VERSION 5.7 ;
BUSBITCHARS "[]" ;
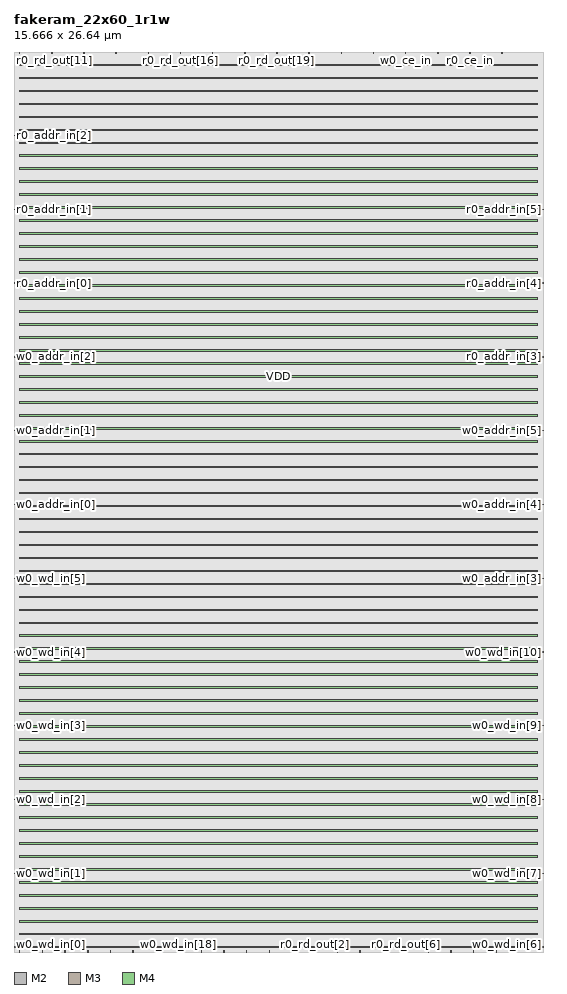
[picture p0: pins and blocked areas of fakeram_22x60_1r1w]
MACRO fakeram_22x60_1r1w
  FOREIGN fakeram_22x60_1r1w 0 0 ;
  SYMMETRY X Y R90 ;
  SIZE 15.666 BY 26.640 ;
  CLASS BLOCK ;
  PIN w0_wd_in[0]
    DIRECTION INPUT ;
    USE SIGNAL ;
    SHAPE ABUTMENT ;
    PORT
      LAYER M2 ;
      RECT 0.000 0.138 0.036 0.150 ;
    END
  END w0_wd_in[0]
  PIN w0_wd_in[1]
    DIRECTION INPUT ;
    USE SIGNAL ;
    SHAPE ABUTMENT ;
    PORT
      LAYER M2 ;
      RECT 0.000 2.322 0.036 2.334 ;
    END
  END w0_wd_in[1]
  PIN w0_wd_in[2]
    DIRECTION INPUT ;
    USE SIGNAL ;
    SHAPE ABUTMENT ;
    PORT
      LAYER M2 ;
      RECT 0.000 4.506 0.036 4.518 ;
    END
  END w0_wd_in[2]
  PIN w0_wd_in[3]
    DIRECTION INPUT ;
    USE SIGNAL ;
    SHAPE ABUTMENT ;
    PORT
      LAYER M2 ;
      RECT 0.000 6.690 0.036 6.702 ;
    END
  END w0_wd_in[3]
  PIN w0_wd_in[4]
    DIRECTION INPUT ;
    USE SIGNAL ;
    SHAPE ABUTMENT ;
    PORT
      LAYER M2 ;
      RECT 0.000 8.874 0.036 8.886 ;
    END
  END w0_wd_in[4]
  PIN w0_wd_in[5]
    DIRECTION INPUT ;
    USE SIGNAL ;
    SHAPE ABUTMENT ;
    PORT
      LAYER M2 ;
      RECT 0.000 11.058 0.036 11.070 ;
    END
  END w0_wd_in[5]
  PIN w0_wd_in[6]
    DIRECTION INPUT ;
    USE SIGNAL ;
    SHAPE ABUTMENT ;
    PORT
      LAYER M2 ;
      RECT 15.630 0.138 15.666 0.150 ;
    END
  END w0_wd_in[6]
  PIN w0_wd_in[7]
    DIRECTION INPUT ;
    USE SIGNAL ;
    SHAPE ABUTMENT ;
    PORT
      LAYER M2 ;
      RECT 15.630 2.322 15.666 2.334 ;
    END
  END w0_wd_in[7]
  PIN w0_wd_in[8]
    DIRECTION INPUT ;
    USE SIGNAL ;
    SHAPE ABUTMENT ;
    PORT
      LAYER M2 ;
      RECT 15.630 4.506 15.666 4.518 ;
    END
  END w0_wd_in[8]
  PIN w0_wd_in[9]
    DIRECTION INPUT ;
    USE SIGNAL ;
    SHAPE ABUTMENT ;
    PORT
      LAYER M2 ;
      RECT 15.630 6.690 15.666 6.702 ;
    END
  END w0_wd_in[9]
  PIN w0_wd_in[10]
    DIRECTION INPUT ;
    USE SIGNAL ;
    SHAPE ABUTMENT ;
    PORT
      LAYER M2 ;
      RECT 15.630 8.874 15.666 8.886 ;
    END
  END w0_wd_in[10]
  PIN w0_wd_in[11]
    DIRECTION INPUT ;
    USE SIGNAL ;
    SHAPE ABUTMENT ;
    PORT
      LAYER M3 ;
      RECT 0.161 0.000 0.175 0.042 ;
    END
  END w0_wd_in[11]
  PIN w0_wd_in[12]
    DIRECTION INPUT ;
    USE SIGNAL ;
    SHAPE ABUTMENT ;
    PORT
      LAYER M3 ;
      RECT 0.833 0.000 0.847 0.042 ;
    END
  END w0_wd_in[12]
  PIN w0_wd_in[13]
    DIRECTION INPUT ;
    USE SIGNAL ;
    SHAPE ABUTMENT ;
    PORT
      LAYER M3 ;
      RECT 1.505 0.000 1.519 0.042 ;
    END
  END w0_wd_in[13]
  PIN w0_wd_in[14]
    DIRECTION INPUT ;
    USE SIGNAL ;
    SHAPE ABUTMENT ;
    PORT
      LAYER M3 ;
      RECT 2.177 0.000 2.191 0.042 ;
    END
  END w0_wd_in[14]
  PIN w0_wd_in[15]
    DIRECTION INPUT ;
    USE SIGNAL ;
    SHAPE ABUTMENT ;
    PORT
      LAYER M3 ;
      RECT 2.849 0.000 2.863 0.042 ;
    END
  END w0_wd_in[15]
  PIN w0_wd_in[16]
    DIRECTION INPUT ;
    USE SIGNAL ;
    SHAPE ABUTMENT ;
    PORT
      LAYER M3 ;
      RECT 3.521 0.000 3.535 0.042 ;
    END
  END w0_wd_in[16]
  PIN w0_wd_in[17]
    DIRECTION INPUT ;
    USE SIGNAL ;
    SHAPE ABUTMENT ;
    PORT
      LAYER M3 ;
      RECT 4.193 0.000 4.207 0.042 ;
    END
  END w0_wd_in[17]
  PIN w0_wd_in[18]
    DIRECTION INPUT ;
    USE SIGNAL ;
    SHAPE ABUTMENT ;
    PORT
      LAYER M3 ;
      RECT 4.865 0.000 4.879 0.042 ;
    END
  END w0_wd_in[18]
  PIN w0_wd_in[19]
    DIRECTION INPUT ;
    USE SIGNAL ;
    SHAPE ABUTMENT ;
    PORT
      LAYER M3 ;
      RECT 5.537 0.000 5.551 0.042 ;
    END
  END w0_wd_in[19]
  PIN w0_wd_in[20]
    DIRECTION INPUT ;
    USE SIGNAL ;
    SHAPE ABUTMENT ;
    PORT
      LAYER M3 ;
      RECT 6.209 0.000 6.223 0.042 ;
    END
  END w0_wd_in[20]
  PIN w0_wd_in[21]
    DIRECTION INPUT ;
    USE SIGNAL ;
    SHAPE ABUTMENT ;
    PORT
      LAYER M3 ;
      RECT 6.881 0.000 6.895 0.042 ;
    END
  END w0_wd_in[21]
  PIN r0_rd_out[0]
    DIRECTION OUTPUT ;
    USE SIGNAL ;
    SHAPE ABUTMENT ;
    PORT
      LAYER M3 ;
      RECT 7.553 0.000 7.567 0.042 ;
    END
  END r0_rd_out[0]
  PIN r0_rd_out[1]
    DIRECTION OUTPUT ;
    USE SIGNAL ;
    SHAPE ABUTMENT ;
    PORT
      LAYER M3 ;
      RECT 8.225 0.000 8.239 0.042 ;
    END
  END r0_rd_out[1]
  PIN r0_rd_out[2]
    DIRECTION OUTPUT ;
    USE SIGNAL ;
    SHAPE ABUTMENT ;
    PORT
      LAYER M3 ;
      RECT 8.897 0.000 8.911 0.042 ;
    END
  END r0_rd_out[2]
  PIN r0_rd_out[3]
    DIRECTION OUTPUT ;
    USE SIGNAL ;
    SHAPE ABUTMENT ;
    PORT
      LAYER M3 ;
      RECT 9.569 0.000 9.583 0.042 ;
    END
  END r0_rd_out[3]
  PIN r0_rd_out[4]
    DIRECTION OUTPUT ;
    USE SIGNAL ;
    SHAPE ABUTMENT ;
    PORT
      LAYER M3 ;
      RECT 10.241 0.000 10.255 0.042 ;
    END
  END r0_rd_out[4]
  PIN r0_rd_out[5]
    DIRECTION OUTPUT ;
    USE SIGNAL ;
    SHAPE ABUTMENT ;
    PORT
      LAYER M3 ;
      RECT 10.913 0.000 10.927 0.042 ;
    END
  END r0_rd_out[5]
  PIN r0_rd_out[6]
    DIRECTION OUTPUT ;
    USE SIGNAL ;
    SHAPE ABUTMENT ;
    PORT
      LAYER M3 ;
      RECT 11.585 0.000 11.599 0.042 ;
    END
  END r0_rd_out[6]
  PIN r0_rd_out[7]
    DIRECTION OUTPUT ;
    USE SIGNAL ;
    SHAPE ABUTMENT ;
    PORT
      LAYER M3 ;
      RECT 12.257 0.000 12.271 0.042 ;
    END
  END r0_rd_out[7]
  PIN r0_rd_out[8]
    DIRECTION OUTPUT ;
    USE SIGNAL ;
    SHAPE ABUTMENT ;
    PORT
      LAYER M3 ;
      RECT 12.929 0.000 12.943 0.042 ;
    END
  END r0_rd_out[8]
  PIN r0_rd_out[9]
    DIRECTION OUTPUT ;
    USE SIGNAL ;
    SHAPE ABUTMENT ;
    PORT
      LAYER M3 ;
      RECT 13.601 0.000 13.615 0.042 ;
    END
  END r0_rd_out[9]
  PIN r0_rd_out[10]
    DIRECTION OUTPUT ;
    USE SIGNAL ;
    SHAPE ABUTMENT ;
    PORT
      LAYER M3 ;
      RECT 14.273 0.000 14.287 0.042 ;
    END
  END r0_rd_out[10]
  PIN r0_rd_out[11]
    DIRECTION OUTPUT ;
    USE SIGNAL ;
    SHAPE ABUTMENT ;
    PORT
      LAYER M3 ;
      RECT 0.161 26.598 0.175 26.640 ;
    END
  END r0_rd_out[11]
  PIN r0_rd_out[12]
    DIRECTION OUTPUT ;
    USE SIGNAL ;
    SHAPE ABUTMENT ;
    PORT
      LAYER M3 ;
      RECT 1.113 26.598 1.127 26.640 ;
    END
  END r0_rd_out[12]
  PIN r0_rd_out[13]
    DIRECTION OUTPUT ;
    USE SIGNAL ;
    SHAPE ABUTMENT ;
    PORT
      LAYER M3 ;
      RECT 2.065 26.598 2.079 26.640 ;
    END
  END r0_rd_out[13]
  PIN r0_rd_out[14]
    DIRECTION OUTPUT ;
    USE SIGNAL ;
    SHAPE ABUTMENT ;
    PORT
      LAYER M3 ;
      RECT 3.017 26.598 3.031 26.640 ;
    END
  END r0_rd_out[14]
  PIN r0_rd_out[15]
    DIRECTION OUTPUT ;
    USE SIGNAL ;
    SHAPE ABUTMENT ;
    PORT
      LAYER M3 ;
      RECT 3.969 26.598 3.983 26.640 ;
    END
  END r0_rd_out[15]
  PIN r0_rd_out[16]
    DIRECTION OUTPUT ;
    USE SIGNAL ;
    SHAPE ABUTMENT ;
    PORT
      LAYER M3 ;
      RECT 4.921 26.598 4.935 26.640 ;
    END
  END r0_rd_out[16]
  PIN r0_rd_out[17]
    DIRECTION OUTPUT ;
    USE SIGNAL ;
    SHAPE ABUTMENT ;
    PORT
      LAYER M3 ;
      RECT 5.873 26.598 5.887 26.640 ;
    END
  END r0_rd_out[17]
  PIN r0_rd_out[18]
    DIRECTION OUTPUT ;
    USE SIGNAL ;
    SHAPE ABUTMENT ;
    PORT
      LAYER M3 ;
      RECT 6.825 26.598 6.839 26.640 ;
    END
  END r0_rd_out[18]
  PIN r0_rd_out[19]
    DIRECTION OUTPUT ;
    USE SIGNAL ;
    SHAPE ABUTMENT ;
    PORT
      LAYER M3 ;
      RECT 7.777 26.598 7.791 26.640 ;
    END
  END r0_rd_out[19]
  PIN r0_rd_out[20]
    DIRECTION OUTPUT ;
    USE SIGNAL ;
    SHAPE ABUTMENT ;
    PORT
      LAYER M3 ;
      RECT 8.729 26.598 8.743 26.640 ;
    END
  END r0_rd_out[20]
  PIN r0_rd_out[21]
    DIRECTION OUTPUT ;
    USE SIGNAL ;
    SHAPE ABUTMENT ;
    PORT
      LAYER M3 ;
      RECT 9.681 26.598 9.695 26.640 ;
    END
  END r0_rd_out[21]
  PIN w0_addr_in[0]
    DIRECTION INPUT ;
    USE SIGNAL ;
    SHAPE ABUTMENT ;
    PORT
      LAYER M2 ;
      RECT 0.000 13.242 0.036 13.254 ;
    END
  END w0_addr_in[0]
  PIN w0_addr_in[1]
    DIRECTION INPUT ;
    USE SIGNAL ;
    SHAPE ABUTMENT ;
    PORT
      LAYER M2 ;
      RECT 0.000 15.426 0.036 15.438 ;
    END
  END w0_addr_in[1]
  PIN w0_addr_in[2]
    DIRECTION INPUT ;
    USE SIGNAL ;
    SHAPE ABUTMENT ;
    PORT
      LAYER M2 ;
      RECT 0.000 17.610 0.036 17.622 ;
    END
  END w0_addr_in[2]
  PIN w0_addr_in[3]
    DIRECTION INPUT ;
    USE SIGNAL ;
    SHAPE ABUTMENT ;
    PORT
      LAYER M2 ;
      RECT 15.630 11.058 15.666 11.070 ;
    END
  END w0_addr_in[3]
  PIN w0_addr_in[4]
    DIRECTION INPUT ;
    USE SIGNAL ;
    SHAPE ABUTMENT ;
    PORT
      LAYER M2 ;
      RECT 15.630 13.242 15.666 13.254 ;
    END
  END w0_addr_in[4]
  PIN w0_addr_in[5]
    DIRECTION INPUT ;
    USE SIGNAL ;
    SHAPE ABUTMENT ;
    PORT
      LAYER M2 ;
      RECT 15.630 15.426 15.666 15.438 ;
    END
  END w0_addr_in[5]
  PIN r0_addr_in[0]
    DIRECTION INPUT ;
    USE SIGNAL ;
    SHAPE ABUTMENT ;
    PORT
      LAYER M2 ;
      RECT 0.000 19.794 0.036 19.806 ;
    END
  END r0_addr_in[0]
  PIN r0_addr_in[1]
    DIRECTION INPUT ;
    USE SIGNAL ;
    SHAPE ABUTMENT ;
    PORT
      LAYER M2 ;
      RECT 0.000 21.978 0.036 21.990 ;
    END
  END r0_addr_in[1]
  PIN r0_addr_in[2]
    DIRECTION INPUT ;
    USE SIGNAL ;
    SHAPE ABUTMENT ;
    PORT
      LAYER M2 ;
      RECT 0.000 24.162 0.036 24.174 ;
    END
  END r0_addr_in[2]
  PIN r0_addr_in[3]
    DIRECTION INPUT ;
    USE SIGNAL ;
    SHAPE ABUTMENT ;
    PORT
      LAYER M2 ;
      RECT 15.630 17.610 15.666 17.622 ;
    END
  END r0_addr_in[3]
  PIN r0_addr_in[4]
    DIRECTION INPUT ;
    USE SIGNAL ;
    SHAPE ABUTMENT ;
    PORT
      LAYER M2 ;
      RECT 15.630 19.794 15.666 19.806 ;
    END
  END r0_addr_in[4]
  PIN r0_addr_in[5]
    DIRECTION INPUT ;
    USE SIGNAL ;
    SHAPE ABUTMENT ;
    PORT
      LAYER M2 ;
      RECT 15.630 21.978 15.666 21.990 ;
    END
  END r0_addr_in[5]
  PIN w0_we_in
    DIRECTION INPUT ;
    USE SIGNAL ;
    SHAPE ABUTMENT ;
    PORT
      LAYER M3 ;
      RECT 10.633 26.598 10.647 26.640 ;
    END
  END w0_we_in
  PIN w0_ce_in
    DIRECTION INPUT ;
    USE SIGNAL ;
    SHAPE ABUTMENT ;
    PORT
      LAYER M3 ;
      RECT 11.585 26.598 11.599 26.640 ;
    END
  END w0_ce_in
  PIN w0_clk
    DIRECTION INPUT ;
    USE SIGNAL ;
    SHAPE ABUTMENT ;
    PORT
      LAYER M3 ;
      RECT 12.537 26.598 12.551 26.640 ;
    END
  END w0_clk
  PIN r0_ce_in
    DIRECTION INPUT ;
    USE SIGNAL ;
    SHAPE ABUTMENT ;
    PORT
      LAYER M3 ;
      RECT 13.489 26.598 13.503 26.640 ;
    END
  END r0_ce_in
  PIN r0_clk
    DIRECTION INPUT ;
    USE SIGNAL ;
    SHAPE ABUTMENT ;
    PORT
      LAYER M3 ;
      RECT 14.441 26.598 14.455 26.640 ;
    END
  END r0_clk
  PIN VSS
    DIRECTION INOUT ;
    USE GROUND ;
    PORT
      LAYER M4 ;
      RECT 0.168 0.120 15.498 0.168 ;
      RECT 0.168 0.504 15.498 0.552 ;
      RECT 0.168 0.888 15.498 0.936 ;
      RECT 0.168 1.272 15.498 1.320 ;
      RECT 0.168 1.656 15.498 1.704 ;
      RECT 0.168 2.040 15.498 2.088 ;
      RECT 0.168 2.424 15.498 2.472 ;
      RECT 0.168 2.808 15.498 2.856 ;
      RECT 0.168 3.192 15.498 3.240 ;
      RECT 0.168 3.576 15.498 3.624 ;
      RECT 0.168 3.960 15.498 4.008 ;
      RECT 0.168 4.344 15.498 4.392 ;
      RECT 0.168 4.728 15.498 4.776 ;
      RECT 0.168 5.112 15.498 5.160 ;
      RECT 0.168 5.496 15.498 5.544 ;
      RECT 0.168 5.880 15.498 5.928 ;
      RECT 0.168 6.264 15.498 6.312 ;
      RECT 0.168 6.648 15.498 6.696 ;
      RECT 0.168 7.032 15.498 7.080 ;
      RECT 0.168 7.416 15.498 7.464 ;
      RECT 0.168 7.800 15.498 7.848 ;
      RECT 0.168 8.184 15.498 8.232 ;
      RECT 0.168 8.568 15.498 8.616 ;
      RECT 0.168 8.952 15.498 9.000 ;
      RECT 0.168 9.336 15.498 9.384 ;
      RECT 0.168 9.720 15.498 9.768 ;
      RECT 0.168 10.104 15.498 10.152 ;
      RECT 0.168 10.488 15.498 10.536 ;
      RECT 0.168 10.872 15.498 10.920 ;
      RECT 0.168 11.256 15.498 11.304 ;
      RECT 0.168 11.640 15.498 11.688 ;
      RECT 0.168 12.024 15.498 12.072 ;
      RECT 0.168 12.408 15.498 12.456 ;
      RECT 0.168 12.792 15.498 12.840 ;
      RECT 0.168 13.176 15.498 13.224 ;
      RECT 0.168 13.560 15.498 13.608 ;
      RECT 0.168 13.944 15.498 13.992 ;
      RECT 0.168 14.328 15.498 14.376 ;
      RECT 0.168 14.712 15.498 14.760 ;
      RECT 0.168 15.096 15.498 15.144 ;
      RECT 0.168 15.480 15.498 15.528 ;
      RECT 0.168 15.864 15.498 15.912 ;
      RECT 0.168 16.248 15.498 16.296 ;
      RECT 0.168 16.632 15.498 16.680 ;
      RECT 0.168 17.016 15.498 17.064 ;
      RECT 0.168 17.400 15.498 17.448 ;
      RECT 0.168 17.784 15.498 17.832 ;
      RECT 0.168 18.168 15.498 18.216 ;
      RECT 0.168 18.552 15.498 18.600 ;
      RECT 0.168 18.936 15.498 18.984 ;
      RECT 0.168 19.320 15.498 19.368 ;
      RECT 0.168 19.704 15.498 19.752 ;
      RECT 0.168 20.088 15.498 20.136 ;
      RECT 0.168 20.472 15.498 20.520 ;
      RECT 0.168 20.856 15.498 20.904 ;
      RECT 0.168 21.240 15.498 21.288 ;
      RECT 0.168 21.624 15.498 21.672 ;
      RECT 0.168 22.008 15.498 22.056 ;
      RECT 0.168 22.392 15.498 22.440 ;
      RECT 0.168 22.776 15.498 22.824 ;
      RECT 0.168 23.160 15.498 23.208 ;
      RECT 0.168 23.544 15.498 23.592 ;
      RECT 0.168 23.928 15.498 23.976 ;
      RECT 0.168 24.312 15.498 24.360 ;
      RECT 0.168 24.696 15.498 24.744 ;
      RECT 0.168 25.080 15.498 25.128 ;
      RECT 0.168 25.464 15.498 25.512 ;
      RECT 0.168 25.848 15.498 25.896 ;
      RECT 0.168 26.232 15.498 26.280 ;
    END
  END VSS
  PIN VDD
    DIRECTION INOUT ;
    USE POWER ;
    PORT
      LAYER M4 ;
      RECT 0.168 0.120 15.498 0.168 ;
      RECT 0.168 0.504 15.498 0.552 ;
      RECT 0.168 0.888 15.498 0.936 ;
      RECT 0.168 1.272 15.498 1.320 ;
      RECT 0.168 1.656 15.498 1.704 ;
      RECT 0.168 2.040 15.498 2.088 ;
      RECT 0.168 2.424 15.498 2.472 ;
      RECT 0.168 2.808 15.498 2.856 ;
      RECT 0.168 3.192 15.498 3.240 ;
      RECT 0.168 3.576 15.498 3.624 ;
      RECT 0.168 3.960 15.498 4.008 ;
      RECT 0.168 4.344 15.498 4.392 ;
      RECT 0.168 4.728 15.498 4.776 ;
      RECT 0.168 5.112 15.498 5.160 ;
      RECT 0.168 5.496 15.498 5.544 ;
      RECT 0.168 5.880 15.498 5.928 ;
      RECT 0.168 6.264 15.498 6.312 ;
      RECT 0.168 6.648 15.498 6.696 ;
      RECT 0.168 7.032 15.498 7.080 ;
      RECT 0.168 7.416 15.498 7.464 ;
      RECT 0.168 7.800 15.498 7.848 ;
      RECT 0.168 8.184 15.498 8.232 ;
      RECT 0.168 8.568 15.498 8.616 ;
      RECT 0.168 8.952 15.498 9.000 ;
      RECT 0.168 9.336 15.498 9.384 ;
      RECT 0.168 9.720 15.498 9.768 ;
      RECT 0.168 10.104 15.498 10.152 ;
      RECT 0.168 10.488 15.498 10.536 ;
      RECT 0.168 10.872 15.498 10.920 ;
      RECT 0.168 11.256 15.498 11.304 ;
      RECT 0.168 11.640 15.498 11.688 ;
      RECT 0.168 12.024 15.498 12.072 ;
      RECT 0.168 12.408 15.498 12.456 ;
      RECT 0.168 12.792 15.498 12.840 ;
      RECT 0.168 13.176 15.498 13.224 ;
      RECT 0.168 13.560 15.498 13.608 ;
      RECT 0.168 13.944 15.498 13.992 ;
      RECT 0.168 14.328 15.498 14.376 ;
      RECT 0.168 14.712 15.498 14.760 ;
      RECT 0.168 15.096 15.498 15.144 ;
      RECT 0.168 15.480 15.498 15.528 ;
      RECT 0.168 15.864 15.498 15.912 ;
      RECT 0.168 16.248 15.498 16.296 ;
      RECT 0.168 16.632 15.498 16.680 ;
      RECT 0.168 17.016 15.498 17.064 ;
      RECT 0.168 17.400 15.498 17.448 ;
      RECT 0.168 17.784 15.498 17.832 ;
      RECT 0.168 18.168 15.498 18.216 ;
      RECT 0.168 18.552 15.498 18.600 ;
      RECT 0.168 18.936 15.498 18.984 ;
      RECT 0.168 19.320 15.498 19.368 ;
      RECT 0.168 19.704 15.498 19.752 ;
      RECT 0.168 20.088 15.498 20.136 ;
      RECT 0.168 20.472 15.498 20.520 ;
      RECT 0.168 20.856 15.498 20.904 ;
      RECT 0.168 21.240 15.498 21.288 ;
      RECT 0.168 21.624 15.498 21.672 ;
      RECT 0.168 22.008 15.498 22.056 ;
      RECT 0.168 22.392 15.498 22.440 ;
      RECT 0.168 22.776 15.498 22.824 ;
      RECT 0.168 23.160 15.498 23.208 ;
      RECT 0.168 23.544 15.498 23.592 ;
      RECT 0.168 23.928 15.498 23.976 ;
      RECT 0.168 24.312 15.498 24.360 ;
      RECT 0.168 24.696 15.498 24.744 ;
      RECT 0.168 25.080 15.498 25.128 ;
      RECT 0.168 25.464 15.498 25.512 ;
      RECT 0.168 25.848 15.498 25.896 ;
      RECT 0.168 26.232 15.498 26.280 ;
    END
  END VDD
  OBS
    LAYER M1 ;
    RECT 0 0 15.666 26.640 ;
    LAYER M2 ;
    RECT 0 0 15.666 26.640 ;
    LAYER M3 ;
    RECT 0 0 15.666 26.640 ;
    LAYER M4 ;
    RECT 0 0 15.666 26.640 ;
  END
END fakeram_22x60_1r1w

END LIBRARY
